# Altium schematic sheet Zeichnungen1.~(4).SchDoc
size A4

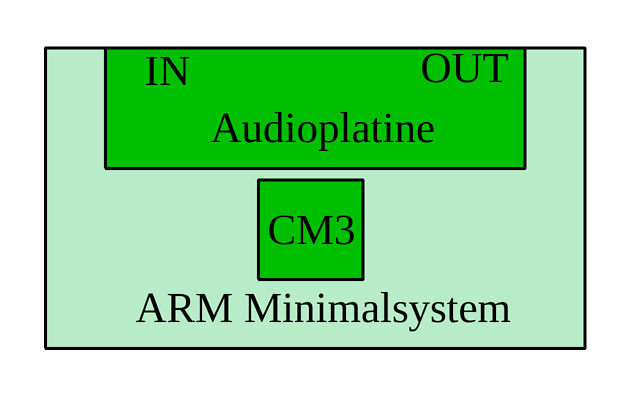
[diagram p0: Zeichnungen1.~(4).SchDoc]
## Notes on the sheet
- IN
- Audioplatine
- OUT
- CM3
- ARM Minimalsystem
